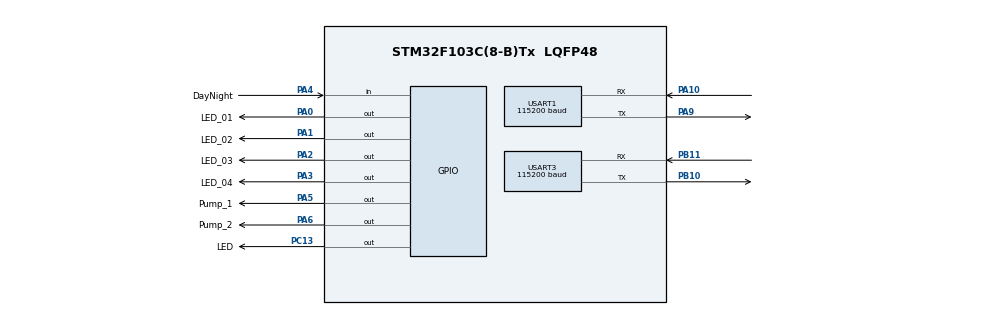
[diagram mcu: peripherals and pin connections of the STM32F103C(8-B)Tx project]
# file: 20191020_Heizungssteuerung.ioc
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Dma.Request0=USART1_TX
Dma.Request1=USART1_RX
Dma.Request2=USART3_RX
Dma.Request3=USART3_TX
Dma.USART1_RX.1.Direction=DMA_PERIPH_TO_MEMORY
Dma.USART1_RX.1.Instance=DMA1_Channel5
Dma.USART1_RX.1.MemDataAlignment=DMA_MDATAALIGN_BYTE
Dma.USART1_RX.1.MemInc=DMA_MINC_ENABLE
Dma.USART1_RX.1.Mode=DMA_CIRCULAR
Dma.USART1_RX.1.PeriphDataAlignment=DMA_PDATAALIGN_BYTE
Dma.USART1_RX.1.PeriphInc=DMA_PINC_DISABLE
Dma.USART1_RX.1.Priority=DMA_PRIORITY_LOW
Dma.USART1_TX.0.Direction=DMA_MEMORY_TO_PERIPH
Dma.USART1_TX.0.Instance=DMA1_Channel4
Dma.USART1_TX.0.MemDataAlignment=DMA_MDATAALIGN_BYTE
Dma.USART1_TX.0.MemInc=DMA_MINC_ENABLE
Dma.USART1_TX.0.Mode=DMA_NORMAL
Dma.USART1_TX.0.PeriphDataAlignment=DMA_PDATAALIGN_BYTE
Dma.USART1_TX.0.PeriphInc=DMA_PINC_DISABLE
Dma.USART1_TX.0.Priority=DMA_PRIORITY_LOW
Dma.USART3_RX.2.Direction=DMA_PERIPH_TO_MEMORY
Dma.USART3_RX.2.Instance=DMA1_Channel3
Dma.USART3_RX.2.MemDataAlignment=DMA_MDATAALIGN_BYTE
Dma.USART3_RX.2.MemInc=DMA_MINC_ENABLE
Dma.USART3_RX.2.Mode=DMA_CIRCULAR
Dma.USART3_RX.2.PeriphDataAlignment=DMA_PDATAALIGN_BYTE
Dma.USART3_RX.2.PeriphInc=DMA_PINC_DISABLE
Dma.USART3_RX.2.Priority=DMA_PRIORITY_LOW
Dma.USART3_TX.3.Direction=DMA_MEMORY_TO_PERIPH
Dma.USART3_TX.3.Instance=DMA1_Channel2
Dma.USART3_TX.3.MemDataAlignment=DMA_MDATAALIGN_BYTE
Dma.USART3_TX.3.MemInc=DMA_MINC_ENABLE
Dma.USART3_TX.3.Mode=DMA_NORMAL
Dma.USART3_TX.3.PeriphDataAlignment=DMA_PDATAALIGN_BYTE
Dma.USART3_TX.3.PeriphInc=DMA_PINC_DISABLE
Dma.USART3_TX.3.Priority=DMA_PRIORITY_LOW
FREERTOS.MEMORY_ALLOCATION=2
FREERTOS.Tasks01=controlTsk,0,128,StartControlTsk,As weak,NULL,Static,controlTskBuffer,controlTskControlBlock;displayTsk,0,128,StartDisplayTsk,As external,NULL,Static,displayTskBuffer,displayTskControlBlock
FREERTOS.configTICK_RATE_HZ=1000
Mcu.Family=STM32F1
Mcu.Name=STM32F103C(8-B)Tx
Mcu.Package=LQFP48
NVIC.DMA1_Channel2_IRQn=true\:5\:0\:false\:false\:true\:true\:false\:true
NVIC.DMA1_Channel3_IRQn=true\:5\:0\:false\:false\:true\:true\:false\:true
NVIC.DMA1_Channel4_IRQn=true\:5\:0\:false\:false\:true\:true\:false\:true
NVIC.DMA1_Channel5_IRQn=true\:5\:0\:false\:false\:true\:true\:false\:true
NVIC.PriorityGroup=NVIC_PRIORITYGROUP_4
NVIC.TIM1_UP_IRQn=true\:0\:0\:false\:false\:true\:false\:false\:true
NVIC.TimeBase=TIM1_UP_IRQn
NVIC.TimeBaseIP=TIM1
NVIC.USART1_IRQn=true\:5\:0\:false\:false\:true\:true\:true\:true
NVIC.USART3_IRQn=true\:5\:0\:false\:false\:true\:true\:true\:true
PA0-WKUP.GPIO_Label=LED_01
PA0-WKUP.Signal=GPIO_Output
PA1.GPIO_Label=LED_02
PA1.Signal=GPIO_Output
PA10.Mode=Asynchronous
PA10.Signal=USART1_RX
PA13.Mode=Serial_Wire
PA13.Signal=SYS_JTMS-SWDIO
PA14.Mode=Serial_Wire
PA14.Signal=SYS_JTCK-SWCLK
PA2.GPIO_Label=LED_03
PA2.Signal=GPIO_Output
PA3.GPIO_Label=LED_04
PA3.Signal=GPIO_Output
PA4.GPIO_Label=DayNight
PA4.Signal=GPIO_Input
PA5.GPIO_Label=Pump_1
PA5.Signal=GPIO_Output
PA6.GPIO_Label=Pump_2
PA6.Signal=GPIO_Output
PA9.Mode=Asynchronous
PA9.Signal=USART1_TX
PB10.Mode=Asynchronous
PB10.Signal=USART3_TX
PB11.Mode=Asynchronous
PB11.Signal=USART3_RX
PC13-TAMPER-RTC.GPIO_Label=LED
PC13-TAMPER-RTC.Signal=GPIO_Output
PC14-OSC32_IN.Mode=LSE-External-Oscillator
PC14-OSC32_IN.Signal=RCC_OSC32_IN
PC15-OSC32_OUT.Mode=LSE-External-Oscillator
PC15-OSC32_OUT.Signal=RCC_OSC32_OUT
PD0-OSC_IN.Mode=HSE-External-Oscillator
PD0-OSC_IN.Signal=RCC_OSC_IN
PD1-OSC_OUT.Mode=HSE-External-Oscillator
PD1-OSC_OUT.Signal=RCC_OSC_OUT
ProjectManager.HeapSize=0x200
ProjectManager.StackSize=0x400
ProjectManager.TargetToolchain=SW4STM32
RCC.AHBFreq_Value=16000000
RCC.APB1CLKDivider=RCC_HCLK_DIV2
RCC.APB1Freq_Value=8000000
RCC.APB1TimFreq_Value=16000000
RCC.APB2Freq_Value=16000000
RCC.APB2TimFreq_Value=16000000
RCC.HCLKFreq_Value=16000000
RCC.PLLSourceVirtual=RCC_PLLSOURCE_HSE
RCC.RTCClockSelection=RCC_RTCCLKSOURCE_LSE
RCC.SYSCLKFreq_VALUE=16000000
RCC.SYSCLKSource=RCC_SYSCLKSOURCE_PLLCLK
RCC.USBFreq_Value=16000000
RTC.Date=7
RTC.Month=RTC_MONTH_AUGUST
RTC.Year=18
USART1.BaudRate=115200
USART1.Parity=PARITY_NONE
USART1.VirtualMode=VM_ASYNC
USART1.WordLength=WORDLENGTH_8B
USART3.BaudRate=115200
USART3.VirtualMode=VM_ASYNC
VP_FREERTOS_VS_CMSIS_V1.Mode=CMSIS_V1
VP_RTC_No_RTC_Output.Mode=RTC_OUT_NO
VP_RTC_VS_RTC_Activate.Mode=RTC_Enabled
VP_RTC_VS_RTC_Calendar.Mode=RTC_Calendar
VP_SYS_VS_tim1.Mode=TIM1
board=cube

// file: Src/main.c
/* USER CODE BEGIN Header */
/**
  ******************************************************************************
  * @file           : main.c
  * @brief          : Main program body
  ******************************************************************************
  * @attention
  *
  * <h2><center>&copy; Copyright (c) 2019 STMicroelectronics.
  * All rights reserved.</center></h2>
  *
  * This software component is licensed by ST under Ultimate Liberty license
  * SLA0044, the "License"; You may not use this file except in compliance with
  * the License. You may obtain a copy of the License at:
  *                             www.st.com/SLA0044
  *
  ******************************************************************************
  */
/* USER CODE END Header */

#include "main.h"
#include "cmsis_os.h"

/* USER CODE BEGIN Includes */

#include "../Framework/Instances/Common.h"
#include "../Framework/System/uart_printf.h"

/* USER CODE END Includes */

CRC_HandleTypeDef hcrc;

RTC_HandleTypeDef hrtc;

UART_HandleTypeDef huart1;
UART_HandleTypeDef huart3;
DMA_HandleTypeDef hdma_usart1_tx;
DMA_HandleTypeDef hdma_usart1_rx;
DMA_HandleTypeDef hdma_usart3_rx;
DMA_HandleTypeDef hdma_usart3_tx;

osThreadId controlTskHandle;
uint32_t controlTskBuffer[ 128 ];
osStaticThreadDef_t controlTskControlBlock;
osThreadId displayTskHandle;
uint32_t displayTskBuffer[ 128 ];
osStaticThreadDef_t displayTskControlBlock;
/* USER CODE BEGIN PV */
/* Private variables ---------------------------------------------------------*/

/* USER CODE END PV */

void SystemClock_Config(void);
static void MX_GPIO_Init(void);
static void MX_DMA_Init(void);
static void MX_RTC_Init(void);
static void MX_USART1_UART_Init(void);
static void MX_USART3_UART_Init(void);
static void MX_CRC_Init(void);
void StartControlTsk(void const * argument);
extern void StartDisplayTsk(void const * argument);

/* USER CODE BEGIN PFP */
/* Private function prototypes -----------------------------------------------*/
void SystemClock_Config(void);
static void MX_GPIO_Init(void);
static void MX_DMA_Init(void);
static void MX_RTC_Init(void);
static void MX_USART1_UART_Init(void);
static void MX_USART3_UART_Init(void);
void StartControlTsk(void const * argument);
extern void StartDisplayTsk(void const * argument);

/* USER CODE END PFP */

/* USER CODE BEGIN 0 */

UART_HandleTypeDef* get_huart1(void) 		{ return &huart1; 	}
UART_HandleTypeDef* get_huart3(void) 		{ return &huart3; 	}

RTC_HandleTypeDef*	get_rtc(void) 			{ return &hrtc;	  	}
CRC_HandleTypeDef*  get_crc(void)			{ return &hcrc;		}
osThreadId* 		get_controlTask(void)	{ return &controlTskHandle; }
osThreadId* 		get_displayTask(void)	{ return &displayTskHandle;}

/* USER CODE END 0 */

int main(void)
{

  /* MCU Configuration--------------------------------------------------------*/

  /* Reset of all peripherals, Initializes the Flash interface and the Systick. */
  HAL_Init();

  /* Configure the system clock */
  SystemClock_Config();

  /* USER CODE BEGIN SysInit */
  HAL_Delay(1000);
  /* USER CODE END SysInit */

  /* Initialize all configured peripherals */
  MX_GPIO_Init();
  MX_DMA_Init();
  MX_RTC_Init();
  MX_USART1_UART_Init();
  MX_USART3_UART_Init();
  MX_CRC_Init();

  /* USER CODE BEGIN RTOS_QUEUES */
  /* add queues, ... */

  // Workaround hanging usart-dma
  // We must set priority to some level, other than 0, to avoid assertion fails with
  // cmsis core.
  HAL_NVIC_SetPriority(USART1_IRQn, 15, 0);
  HAL_NVIC_EnableIRQ(USART1_IRQn);
  //HAL_NVIC_SetPriority(USART2_IRQn, 15, 0);
  //HAL_NVIC_EnableIRQ(USART2_IRQn);
  HAL_NVIC_SetPriority(USART3_IRQn, 15, 0);
  HAL_NVIC_EnableIRQ(USART3_IRQn);
  common_init();

  /* USER CODE END RTOS_QUEUES */

  /* Create the thread(s) */
  /* definition and creation of controlTsk */
  osThreadStaticDef(controlTsk, StartControlTsk, osPriorityNormal, 0, 128, controlTskBuffer, &controlTskControlBlock);
  controlTskHandle = osThreadCreate(osThread(controlTsk), NULL);

  /* definition and creation of displayTsk */
  osThreadStaticDef(displayTsk, StartDisplayTsk, osPriorityNormal, 0, 128, displayTskBuffer, &displayTskControlBlock);
  displayTskHandle = osThreadCreate(osThread(displayTsk), NULL);

  /* Start scheduler */
  osKernelStart();

  /* We should never get here as control is now taken by the scheduler */

  /* Infinite loop */
  /* USER CODE BEGIN WHILE */

  tx_printf("Trapped!\n");

  while (1)
  {

    /* USER CODE END WHILE */

  }
}

void SystemClock_Config(void)
{
  RCC_OscInitTypeDef RCC_OscInitStruct = {0};
  RCC_ClkInitTypeDef RCC_ClkInitStruct = {0};
  RCC_PeriphCLKInitTypeDef PeriphClkInit = {0};

  /** Initializes the CPU, AHB and APB busses clocks
  */
  RCC_OscInitStruct.OscillatorType = RCC_OSCILLATORTYPE_HSI|RCC_OSCILLATORTYPE_LSE;
  RCC_OscInitStruct.LSEState = RCC_LSE_ON;
  RCC_OscInitStruct.HSIState = RCC_HSI_ON;
  RCC_OscInitStruct.HSICalibrationValue = RCC_HSICALIBRATION_DEFAULT;
  RCC_OscInitStruct.PLL.PLLState = RCC_PLL_NONE;
  if (HAL_RCC_OscConfig(&RCC_OscInitStruct) != HAL_OK)
  {
    Error_Handler();
  }
  /** Initializes the CPU, AHB and APB busses clocks
  */
  RCC_ClkInitStruct.ClockType = RCC_CLOCKTYPE_HCLK|RCC_CLOCKTYPE_SYSCLK
                              |RCC_CLOCKTYPE_PCLK1|RCC_CLOCKTYPE_PCLK2;
  RCC_ClkInitStruct.SYSCLKSource = RCC_SYSCLKSOURCE_HSI;
  RCC_ClkInitStruct.AHBCLKDivider = RCC_SYSCLK_DIV1;
  RCC_ClkInitStruct.APB1CLKDivider = RCC_HCLK_DIV2;
  RCC_ClkInitStruct.APB2CLKDivider = RCC_HCLK_DIV1;

  if (HAL_RCC_ClockConfig(&RCC_ClkInitStruct, FLASH_LATENCY_0) != HAL_OK)
  {
    Error_Handler();
  }
  PeriphClkInit.PeriphClockSelection = RCC_PERIPHCLK_RTC;
  PeriphClkInit.RTCClockSelection = RCC_RTCCLKSOURCE_LSE;
  if (HAL_RCCEx_PeriphCLKConfig(&PeriphClkInit) != HAL_OK)
  {
    Error_Handler();
  }
}

static void MX_CRC_Init(void)
{

  hcrc.Instance = CRC;
  if (HAL_CRC_Init(&hcrc) != HAL_OK)
  {
    Error_Handler();
  }

}

static void MX_RTC_Init(void)
{

  RTC_TimeTypeDef sTime = {0};
  RTC_DateTypeDef DateToUpdate = {0};

  /** Initialize RTC Only
  */
  hrtc.Instance = RTC;
  hrtc.Init.AsynchPrediv = RTC_AUTO_1_SECOND;
  hrtc.Init.OutPut = RTC_OUTPUTSOURCE_NONE;
  if (HAL_RTC_Init(&hrtc) != HAL_OK)
  {
    Error_Handler();
  }

  /* USER CODE BEGIN Check_RTC_BKUP */
  // we don't want to init RTC values
  return;

  /* USER CODE END Check_RTC_BKUP */

  /** Initialize RTC and set the Time and Date
  */
  sTime.Hours = 0x0;
  sTime.Minutes = 0x0;
  sTime.Seconds = 0x0;

  if (HAL_RTC_SetTime(&hrtc, &sTime, RTC_FORMAT_BCD) != HAL_OK)
  {
    Error_Handler();
  }
  DateToUpdate.WeekDay = RTC_WEEKDAY_MONDAY;
  DateToUpdate.Month = RTC_MONTH_AUGUST;
  DateToUpdate.Date = 0x7;
  DateToUpdate.Year = 0x18;

  if (HAL_RTC_SetDate(&hrtc, &DateToUpdate, RTC_FORMAT_BCD) != HAL_OK)
  {
    Error_Handler();
  }

}

static void MX_USART1_UART_Init(void)
{

  huart1.Instance = USART1;
  huart1.Init.BaudRate = 115200;
  huart1.Init.WordLength = UART_WORDLENGTH_8B;
  huart1.Init.StopBits = UART_STOPBITS_1;
  huart1.Init.Parity = UART_PARITY_NONE;
  huart1.Init.Mode = UART_MODE_TX_RX;
  huart1.Init.HwFlowCtl = UART_HWCONTROL_NONE;
  huart1.Init.OverSampling = UART_OVERSAMPLING_16;
  if (HAL_UART_Init(&huart1) != HAL_OK)
  {
    Error_Handler();
  }

}

static void MX_USART3_UART_Init(void)
{

  huart3.Instance = USART3;
  huart3.Init.BaudRate = 115200;
  huart3.Init.WordLength = UART_WORDLENGTH_8B;
  huart3.Init.StopBits = UART_STOPBITS_1;
  huart3.Init.Parity = UART_PARITY_NONE;
  huart3.Init.Mode = UART_MODE_TX_RX;
  huart3.Init.HwFlowCtl = UART_HWCONTROL_NONE;
  huart3.Init.OverSampling = UART_OVERSAMPLING_16;
  if (HAL_UART_Init(&huart3) != HAL_OK)
  {
    Error_Handler();
  }

}

static void MX_DMA_Init(void)
{
  /* DMA controller clock enable */
  __HAL_RCC_DMA1_CLK_ENABLE();

  /* DMA interrupt init */
  /* DMA1_Channel2_IRQn interrupt configuration */
  HAL_NVIC_SetPriority(DMA1_Channel2_IRQn, 5, 0);
  HAL_NVIC_EnableIRQ(DMA1_Channel2_IRQn);
  /* DMA1_Channel3_IRQn interrupt configuration */
  HAL_NVIC_SetPriority(DMA1_Channel3_IRQn, 5, 0);
  HAL_NVIC_EnableIRQ(DMA1_Channel3_IRQn);
  /* DMA1_Channel4_IRQn interrupt configuration */
  HAL_NVIC_SetPriority(DMA1_Channel4_IRQn, 5, 0);
  HAL_NVIC_EnableIRQ(DMA1_Channel4_IRQn);
  /* DMA1_Channel5_IRQn interrupt configuration */
  HAL_NVIC_SetPriority(DMA1_Channel5_IRQn, 5, 0);
  HAL_NVIC_EnableIRQ(DMA1_Channel5_IRQn);

}

static void MX_GPIO_Init(void)
{
  GPIO_InitTypeDef GPIO_InitStruct = {0};

  /* GPIO Ports Clock Enable */
  __HAL_RCC_GPIOC_CLK_ENABLE();
  __HAL_RCC_GPIOD_CLK_ENABLE();
  __HAL_RCC_GPIOA_CLK_ENABLE();
  __HAL_RCC_GPIOB_CLK_ENABLE();

  /*Configure GPIO pin Output Level */
  HAL_GPIO_WritePin(LED_GPIO_Port, LED_Pin, GPIO_PIN_RESET);

  /*Configure GPIO pin Output Level */
  HAL_GPIO_WritePin(GPIOA, LED_01_Pin|LED_02_Pin|LED_03_Pin|LED_04_Pin
                          |Pump_1_Pin|Pump_2_Pin, GPIO_PIN_RESET);

  /*Configure GPIO pin : LED_Pin */
  GPIO_InitStruct.Pin = LED_Pin;
  GPIO_InitStruct.Mode = GPIO_MODE_OUTPUT_PP;
  GPIO_InitStruct.Pull = GPIO_NOPULL;
  GPIO_InitStruct.Speed = GPIO_SPEED_FREQ_LOW;
  HAL_GPIO_Init(LED_GPIO_Port, &GPIO_InitStruct);

  /*Configure GPIO pins : LED_01_Pin LED_02_Pin LED_03_Pin LED_04_Pin
                           Pump_1_Pin Pump_2_Pin */
  GPIO_InitStruct.Pin = LED_01_Pin|LED_02_Pin|LED_03_Pin|LED_04_Pin
                          |Pump_1_Pin|Pump_2_Pin;
  GPIO_InitStruct.Mode = GPIO_MODE_OUTPUT_PP;
  GPIO_InitStruct.Pull = GPIO_NOPULL;
  GPIO_InitStruct.Speed = GPIO_SPEED_FREQ_LOW;
  HAL_GPIO_Init(GPIOA, &GPIO_InitStruct);

  /*Configure GPIO pin : DayNight_Pin */
  GPIO_InitStruct.Pin = DayNight_Pin;
  GPIO_InitStruct.Mode = GPIO_MODE_INPUT;
  GPIO_InitStruct.Pull = GPIO_NOPULL;
  HAL_GPIO_Init(DayNight_GPIO_Port, &GPIO_InitStruct);

}

__weak void StartControlTsk(void const * argument)
{

  for(;;)
  {
    osDelay(1);
  }
}

void HAL_TIM_PeriodElapsedCallback(TIM_HandleTypeDef *htim)
{
  if (htim->Instance == TIM1) {
    HAL_IncTick();
  }
}

void Error_Handler(void)
{
  /* USER CODE BEGIN Error_Handler_Debug */
	tx_printf("ERROR_HANDLER called\n");
  /* User can add his own implementation to report the HAL error return state */
  while(1)
  {
  }
  /* USER CODE END Error_Handler_Debug */
}

#ifdef  USE_FULL_ASSERT
/**
  * @brief  Reports the name of the source file and the source line number
  *         where the assert_param error has occurred.
  * @param  file: pointer to the source file name
  * @param  line: assert_param error line source number
  * @retval None
  */
void assert_failed(uint8_t *file, uint32_t line)
{
  /* USER CODE BEGIN 6 */
	tx_printf("assert_failed: line %i, %s\n", line, file);
  /* User can add his own implementation to report the file name and line number,
     tex: printf("Wrong parameters value: file %s on line %d\r\n", file, line) */
  /* USER CODE END 6 */
}
#endif /* USE_FULL_ASSERT */

/************************ (C) COPYRIGHT STMicroelectronics *****END OF FILE****/

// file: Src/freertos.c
/* USER CODE BEGIN Header */
/**
  ******************************************************************************
  * File Name          : freertos.c
  * Description        : Code for freertos applications
  ******************************************************************************
  * This notice applies to any and all portions of this file
  * that are not between comment pairs USER CODE BEGIN and
  * USER CODE END. Other portions of this file, whether
  * inserted by the user or by software development tools
  * are owned by their respective copyright owners.
  *
  * Copyright (c) 2019 STMicroelectronics International N.V.
  * All rights reserved.
  *
  * Redistribution and use in source and binary forms, with or without
  * modification, are permitted, provided that the following conditions are met:
  *
  * 1. Redistribution of source code must retain the above copyright notice,
  *    this list of conditions and the following disclaimer.
  * 2. Redistributions in binary form must reproduce the above copyright notice,
  *    this list of conditions and the following disclaimer in the documentation
  *    and/or other materials provided with the distribution.
  * 3. Neither the name of STMicroelectronics nor the names of other
  *    contributors to this software may be used to endorse or promote products
  *    derived from this software without specific written permission.
  * 4. This software, including modifications and/or derivative works of this
  *    software, must execute solely and exclusively on microcontroller or
  *    microprocessor devices manufactured by or for STMicroelectronics.
  * 5. Redistribution and use of this software other than as permitted under
  *    this license is void and will automatically terminate your rights under
  *    this license.
  *
  * THIS SOFTWARE IS PROVIDED BY STMICROELECTRONICS AND CONTRIBUTORS "AS IS"
  * AND ANY EXPRESS, IMPLIED OR STATUTORY WARRANTIES, INCLUDING, BUT NOT
  * LIMITED TO, THE IMPLIED WARRANTIES OF MERCHANTABILITY, FITNESS FOR A
  * PARTICULAR PURPOSE AND NON-INFRINGEMENT OF THIRD PARTY INTELLECTUAL PROPERTY
  * RIGHTS ARE DISCLAIMED TO THE FULLEST EXTENT PERMITTED BY LAW. IN NO EVENT
  * SHALL STMICROELECTRONICS OR CONTRIBUTORS BE LIABLE FOR ANY DIRECT, INDIRECT,
  * INCIDENTAL, SPECIAL, EXEMPLARY, OR CONSEQUENTIAL DAMAGES (INCLUDING, BUT NOT
  * LIMITED TO, PROCUREMENT OF SUBSTITUTE GOODS OR SERVICES; LOSS OF USE, DATA,
  * OR PROFITS; OR BUSINESS INTERRUPTION) HOWEVER CAUSED AND ON ANY THEORY OF
  * LIABILITY, WHETHER IN CONTRACT, STRICT LIABILITY, OR TORT (INCLUDING
  * NEGLIGENCE OR OTHERWISE) ARISING IN ANY WAY OUT OF THE USE OF THIS SOFTWARE,
  * EVEN IF ADVISED OF THE POSSIBILITY OF SUCH DAMAGE.
  *
  ******************************************************************************
  */
/* USER CODE END Header */

#include "FreeRTOS.h"
#include "task.h"
#include "main.h"

/* GetIdleTaskMemory prototype (linked to static allocation support) */
void vApplicationGetIdleTaskMemory( StaticTask_t **ppxIdleTaskTCBBuffer, StackType_t **ppxIdleTaskStackBuffer, uint32_t *pulIdleTaskStackSize );

/* USER CODE BEGIN GET_IDLE_TASK_MEMORY */
static StaticTask_t xIdleTaskTCBBuffer;
static StackType_t xIdleStack[configMINIMAL_STACK_SIZE];

void vApplicationGetIdleTaskMemory( StaticTask_t **ppxIdleTaskTCBBuffer, StackType_t **ppxIdleTaskStackBuffer, uint32_t *pulIdleTaskStackSize )
{
  *ppxIdleTaskTCBBuffer = &xIdleTaskTCBBuffer;
  *ppxIdleTaskStackBuffer = &xIdleStack[0];
  *pulIdleTaskStackSize = configMINIMAL_STACK_SIZE;
  /* place for user code */
}
/* USER CODE END GET_IDLE_TASK_MEMORY */

/************************ (C) COPYRIGHT STMicroelectronics *****END OF FILE****/
